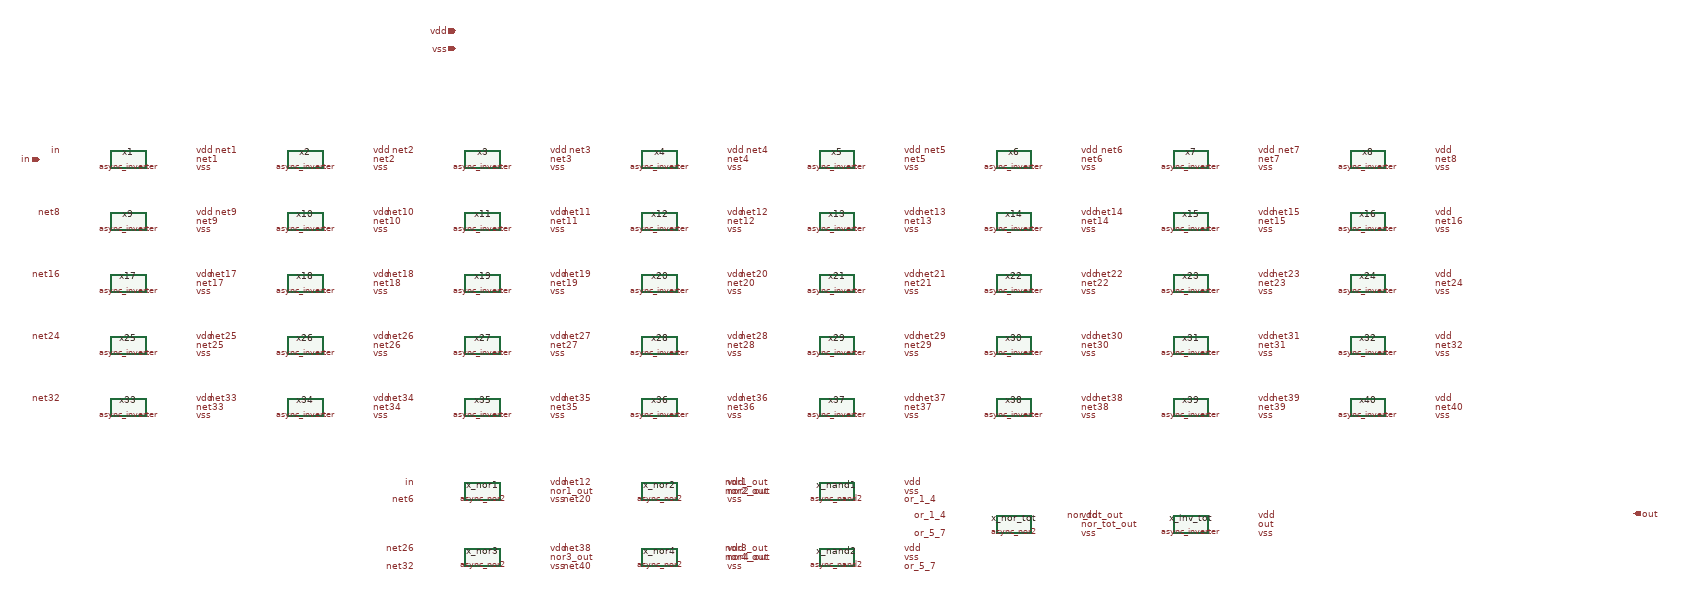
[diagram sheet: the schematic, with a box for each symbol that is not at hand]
v {xschem version=3.4.8RC file_version=1.3}
G {}
K {}
V {}
S {}
F {}
E {}
C {ipin.sym} -1600 -400 0 0 {name=p_in lab=in}
C {iopin.sym} -660 -690 0 0 {name=p_vdd lab=vdd}
C {iopin.sym} -660 -650 0 0 {name=p_vss lab=vss}
C {opin.sym} 2000 400 0 0 {name=p_out lab=out}
C {sar_adc/blocks/async_sar/async_inverter.sym} -1400 -400 0 0 {name=x1}
C {lab_wire.sym} -1550 -420 0 0 {name=l_x1_in lab=in}
C {lab_wire.sym} -1250 -400 2 0 {name=l_x1_out lab=net1}
C {lab_wire.sym} -1250 -420 2 0 {name=l_x1_vdd lab=vdd}
C {lab_wire.sym} -1250 -380 2 0 {name=l_x1_vss lab=vss}
C {sar_adc/blocks/async_sar/async_inverter.sym} -1000 -400 0 0 {name=x2}
C {lab_wire.sym} -1150 -420 0 0 {name=l_x2_in lab=net1}
C {lab_wire.sym} -850 -400 2 0 {name=l_x2_out lab=net2}
C {lab_wire.sym} -850 -420 2 0 {name=l_x2_vdd lab=vdd}
C {lab_wire.sym} -850 -380 2 0 {name=l_x2_vss lab=vss}
C {sar_adc/blocks/async_sar/async_inverter.sym} -600 -400 0 0 {name=x3}
C {lab_wire.sym} -750 -420 0 0 {name=l_x3_in lab=net2}
C {lab_wire.sym} -450 -400 2 0 {name=l_x3_out lab=net3}
C {lab_wire.sym} -450 -420 2 0 {name=l_x3_vdd lab=vdd}
C {lab_wire.sym} -450 -380 2 0 {name=l_x3_vss lab=vss}
C {sar_adc/blocks/async_sar/async_inverter.sym} -200 -400 0 0 {name=x4}
C {lab_wire.sym} -350 -420 0 0 {name=l_x4_in lab=net3}
C {lab_wire.sym} -50 -400 2 0 {name=l_x4_out lab=net4}
C {lab_wire.sym} -50 -420 2 0 {name=l_x4_vdd lab=vdd}
C {lab_wire.sym} -50 -380 2 0 {name=l_x4_vss lab=vss}
C {sar_adc/blocks/async_sar/async_inverter.sym} 200 -400 0 0 {name=x5}
C {lab_wire.sym} 50 -420 0 0 {name=l_x5_in lab=net4}
C {lab_wire.sym} 350 -400 2 0 {name=l_x5_out lab=net5}
C {lab_wire.sym} 350 -420 2 0 {name=l_x5_vdd lab=vdd}
C {lab_wire.sym} 350 -380 2 0 {name=l_x5_vss lab=vss}
C {sar_adc/blocks/async_sar/async_inverter.sym} 600 -400 0 0 {name=x6}
C {lab_wire.sym} 450 -420 0 0 {name=l_x6_in lab=net5}
C {lab_wire.sym} 750 -400 2 0 {name=l_x6_out lab=net6}
C {lab_wire.sym} 750 -420 2 0 {name=l_x6_vdd lab=vdd}
C {lab_wire.sym} 750 -380 2 0 {name=l_x6_vss lab=vss}
C {sar_adc/blocks/async_sar/async_inverter.sym} 1000 -400 0 0 {name=x7}
C {lab_wire.sym} 850 -420 0 0 {name=l_x7_in lab=net6}
C {lab_wire.sym} 1150 -400 2 0 {name=l_x7_out lab=net7}
C {lab_wire.sym} 1150 -420 2 0 {name=l_x7_vdd lab=vdd}
C {lab_wire.sym} 1150 -380 2 0 {name=l_x7_vss lab=vss}
C {sar_adc/blocks/async_sar/async_inverter.sym} 1400 -400 0 0 {name=x8}
C {lab_wire.sym} 1250 -420 0 0 {name=l_x8_in lab=net7}
C {lab_wire.sym} 1550 -400 2 0 {name=l_x8_out lab=net8}
C {lab_wire.sym} 1550 -420 2 0 {name=l_x8_vdd lab=vdd}
C {lab_wire.sym} 1550 -380 2 0 {name=l_x8_vss lab=vss}
C {sar_adc/blocks/async_sar/async_inverter.sym} -1400 -260 0 0 {name=x9}
C {lab_wire.sym} -1550 -280 0 0 {name=l_x9_in lab=net8}
C {lab_wire.sym} -1250 -260 2 0 {name=l_x9_out lab=net9}
C {lab_wire.sym} -1250 -280 2 0 {name=l_x9_vdd lab=vdd}
C {lab_wire.sym} -1250 -240 2 0 {name=l_x9_vss lab=vss}
C {sar_adc/blocks/async_sar/async_inverter.sym} -1000 -260 0 0 {name=x10}
C {lab_wire.sym} -1150 -280 0 0 {name=l_x10_in lab=net9}
C {lab_wire.sym} -850 -260 2 0 {name=l_x10_out lab=net10}
C {lab_wire.sym} -850 -280 2 0 {name=l_x10_vdd lab=vdd}
C {lab_wire.sym} -850 -240 2 0 {name=l_x10_vss lab=vss}
C {sar_adc/blocks/async_sar/async_inverter.sym} -600 -260 0 0 {name=x11}
C {lab_wire.sym} -750 -280 0 0 {name=l_x11_in lab=net10}
C {lab_wire.sym} -450 -260 2 0 {name=l_x11_out lab=net11}
C {lab_wire.sym} -450 -280 2 0 {name=l_x11_vdd lab=vdd}
C {lab_wire.sym} -450 -240 2 0 {name=l_x11_vss lab=vss}
C {sar_adc/blocks/async_sar/async_inverter.sym} -200 -260 0 0 {name=x12}
C {lab_wire.sym} -350 -280 0 0 {name=l_x12_in lab=net11}
C {lab_wire.sym} -50 -260 2 0 {name=l_x12_out lab=net12}
C {lab_wire.sym} -50 -280 2 0 {name=l_x12_vdd lab=vdd}
C {lab_wire.sym} -50 -240 2 0 {name=l_x12_vss lab=vss}
C {sar_adc/blocks/async_sar/async_inverter.sym} 200 -260 0 0 {name=x13}
C {lab_wire.sym} 50 -280 0 0 {name=l_x13_in lab=net12}
C {lab_wire.sym} 350 -260 2 0 {name=l_x13_out lab=net13}
C {lab_wire.sym} 350 -280 2 0 {name=l_x13_vdd lab=vdd}
C {lab_wire.sym} 350 -240 2 0 {name=l_x13_vss lab=vss}
C {sar_adc/blocks/async_sar/async_inverter.sym} 600 -260 0 0 {name=x14}
C {lab_wire.sym} 450 -280 0 0 {name=l_x14_in lab=net13}
C {lab_wire.sym} 750 -260 2 0 {name=l_x14_out lab=net14}
C {lab_wire.sym} 750 -280 2 0 {name=l_x14_vdd lab=vdd}
C {lab_wire.sym} 750 -240 2 0 {name=l_x14_vss lab=vss}
C {sar_adc/blocks/async_sar/async_inverter.sym} 1000 -260 0 0 {name=x15}
C {lab_wire.sym} 850 -280 0 0 {name=l_x15_in lab=net14}
C {lab_wire.sym} 1150 -260 2 0 {name=l_x15_out lab=net15}
C {lab_wire.sym} 1150 -280 2 0 {name=l_x15_vdd lab=vdd}
C {lab_wire.sym} 1150 -240 2 0 {name=l_x15_vss lab=vss}
C {sar_adc/blocks/async_sar/async_inverter.sym} 1400 -260 0 0 {name=x16}
C {lab_wire.sym} 1250 -280 0 0 {name=l_x16_in lab=net15}
C {lab_wire.sym} 1550 -260 2 0 {name=l_x16_out lab=net16}
C {lab_wire.sym} 1550 -280 2 0 {name=l_x16_vdd lab=vdd}
C {lab_wire.sym} 1550 -240 2 0 {name=l_x16_vss lab=vss}
C {sar_adc/blocks/async_sar/async_inverter.sym} -1400 -120 0 0 {name=x17}
C {lab_wire.sym} -1550 -140 0 0 {name=l_x17_in lab=net16}
C {lab_wire.sym} -1250 -120 2 0 {name=l_x17_out lab=net17}
C {lab_wire.sym} -1250 -140 2 0 {name=l_x17_vdd lab=vdd}
C {lab_wire.sym} -1250 -100 2 0 {name=l_x17_vss lab=vss}
C {sar_adc/blocks/async_sar/async_inverter.sym} -1000 -120 0 0 {name=x18}
C {lab_wire.sym} -1150 -140 0 0 {name=l_x18_in lab=net17}
C {lab_wire.sym} -850 -120 2 0 {name=l_x18_out lab=net18}
C {lab_wire.sym} -850 -140 2 0 {name=l_x18_vdd lab=vdd}
C {lab_wire.sym} -850 -100 2 0 {name=l_x18_vss lab=vss}
C {sar_adc/blocks/async_sar/async_inverter.sym} -600 -120 0 0 {name=x19}
C {lab_wire.sym} -750 -140 0 0 {name=l_x19_in lab=net18}
C {lab_wire.sym} -450 -120 2 0 {name=l_x19_out lab=net19}
C {lab_wire.sym} -450 -140 2 0 {name=l_x19_vdd lab=vdd}
C {lab_wire.sym} -450 -100 2 0 {name=l_x19_vss lab=vss}
C {sar_adc/blocks/async_sar/async_inverter.sym} -200 -120 0 0 {name=x20}
C {lab_wire.sym} -350 -140 0 0 {name=l_x20_in lab=net19}
C {lab_wire.sym} -50 -120 2 0 {name=l_x20_out lab=net20}
C {lab_wire.sym} -50 -140 2 0 {name=l_x20_vdd lab=vdd}
C {lab_wire.sym} -50 -100 2 0 {name=l_x20_vss lab=vss}
C {sar_adc/blocks/async_sar/async_inverter.sym} 200 -120 0 0 {name=x21}
C {lab_wire.sym} 50 -140 0 0 {name=l_x21_in lab=net20}
C {lab_wire.sym} 350 -120 2 0 {name=l_x21_out lab=net21}
C {lab_wire.sym} 350 -140 2 0 {name=l_x21_vdd lab=vdd}
C {lab_wire.sym} 350 -100 2 0 {name=l_x21_vss lab=vss}
C {sar_adc/blocks/async_sar/async_inverter.sym} 600 -120 0 0 {name=x22}
C {lab_wire.sym} 450 -140 0 0 {name=l_x22_in lab=net21}
C {lab_wire.sym} 750 -120 2 0 {name=l_x22_out lab=net22}
C {lab_wire.sym} 750 -140 2 0 {name=l_x22_vdd lab=vdd}
C {lab_wire.sym} 750 -100 2 0 {name=l_x22_vss lab=vss}
C {sar_adc/blocks/async_sar/async_inverter.sym} 1000 -120 0 0 {name=x23}
C {lab_wire.sym} 850 -140 0 0 {name=l_x23_in lab=net22}
C {lab_wire.sym} 1150 -120 2 0 {name=l_x23_out lab=net23}
C {lab_wire.sym} 1150 -140 2 0 {name=l_x23_vdd lab=vdd}
C {lab_wire.sym} 1150 -100 2 0 {name=l_x23_vss lab=vss}
C {sar_adc/blocks/async_sar/async_inverter.sym} 1400 -120 0 0 {name=x24}
C {lab_wire.sym} 1250 -140 0 0 {name=l_x24_in lab=net23}
C {lab_wire.sym} 1550 -120 2 0 {name=l_x24_out lab=net24}
C {lab_wire.sym} 1550 -140 2 0 {name=l_x24_vdd lab=vdd}
C {lab_wire.sym} 1550 -100 2 0 {name=l_x24_vss lab=vss}
C {sar_adc/blocks/async_sar/async_inverter.sym} -1400 20 0 0 {name=x25}
C {lab_wire.sym} -1550 0 0 0 {name=l_x25_in lab=net24}
C {lab_wire.sym} -1250 20 2 0 {name=l_x25_out lab=net25}
C {lab_wire.sym} -1250 0 2 0 {name=l_x25_vdd lab=vdd}
C {lab_wire.sym} -1250 40 2 0 {name=l_x25_vss lab=vss}
C {sar_adc/blocks/async_sar/async_inverter.sym} -1000 20 0 0 {name=x26}
C {lab_wire.sym} -1150 0 0 0 {name=l_x26_in lab=net25}
C {lab_wire.sym} -850 20 2 0 {name=l_x26_out lab=net26}
C {lab_wire.sym} -850 0 2 0 {name=l_x26_vdd lab=vdd}
C {lab_wire.sym} -850 40 2 0 {name=l_x26_vss lab=vss}
C {sar_adc/blocks/async_sar/async_inverter.sym} -600 20 0 0 {name=x27}
C {lab_wire.sym} -750 0 0 0 {name=l_x27_in lab=net26}
C {lab_wire.sym} -450 20 2 0 {name=l_x27_out lab=net27}
C {lab_wire.sym} -450 0 2 0 {name=l_x27_vdd lab=vdd}
C {lab_wire.sym} -450 40 2 0 {name=l_x27_vss lab=vss}
C {sar_adc/blocks/async_sar/async_inverter.sym} -200 20 0 0 {name=x28}
C {lab_wire.sym} -350 0 0 0 {name=l_x28_in lab=net27}
C {lab_wire.sym} -50 20 2 0 {name=l_x28_out lab=net28}
C {lab_wire.sym} -50 0 2 0 {name=l_x28_vdd lab=vdd}
C {lab_wire.sym} -50 40 2 0 {name=l_x28_vss lab=vss}
C {sar_adc/blocks/async_sar/async_inverter.sym} 200 20 0 0 {name=x29}
C {lab_wire.sym} 50 0 0 0 {name=l_x29_in lab=net28}
C {lab_wire.sym} 350 20 2 0 {name=l_x29_out lab=net29}
C {lab_wire.sym} 350 0 2 0 {name=l_x29_vdd lab=vdd}
C {lab_wire.sym} 350 40 2 0 {name=l_x29_vss lab=vss}
C {sar_adc/blocks/async_sar/async_inverter.sym} 600 20 0 0 {name=x30}
C {lab_wire.sym} 450 0 0 0 {name=l_x30_in lab=net29}
C {lab_wire.sym} 750 20 2 0 {name=l_x30_out lab=net30}
C {lab_wire.sym} 750 0 2 0 {name=l_x30_vdd lab=vdd}
C {lab_wire.sym} 750 40 2 0 {name=l_x30_vss lab=vss}
C {sar_adc/blocks/async_sar/async_inverter.sym} 1000 20 0 0 {name=x31}
C {lab_wire.sym} 850 0 0 0 {name=l_x31_in lab=net30}
C {lab_wire.sym} 1150 20 2 0 {name=l_x31_out lab=net31}
C {lab_wire.sym} 1150 0 2 0 {name=l_x31_vdd lab=vdd}
C {lab_wire.sym} 1150 40 2 0 {name=l_x31_vss lab=vss}
C {sar_adc/blocks/async_sar/async_inverter.sym} 1400 20 0 0 {name=x32}
C {lab_wire.sym} 1250 0 0 0 {name=l_x32_in lab=net31}
C {lab_wire.sym} 1550 20 2 0 {name=l_x32_out lab=net32}
C {lab_wire.sym} 1550 0 2 0 {name=l_x32_vdd lab=vdd}
C {lab_wire.sym} 1550 40 2 0 {name=l_x32_vss lab=vss}
C {sar_adc/blocks/async_sar/async_inverter.sym} -1400 160 0 0 {name=x33}
C {lab_wire.sym} -1550 140 0 0 {name=l_x33_in lab=net32}
C {lab_wire.sym} -1250 160 2 0 {name=l_x33_out lab=net33}
C {lab_wire.sym} -1250 140 2 0 {name=l_x33_vdd lab=vdd}
C {lab_wire.sym} -1250 180 2 0 {name=l_x33_vss lab=vss}
C {sar_adc/blocks/async_sar/async_inverter.sym} -1000 160 0 0 {name=x34}
C {lab_wire.sym} -1150 140 0 0 {name=l_x34_in lab=net33}
C {lab_wire.sym} -850 160 2 0 {name=l_x34_out lab=net34}
C {lab_wire.sym} -850 140 2 0 {name=l_x34_vdd lab=vdd}
C {lab_wire.sym} -850 180 2 0 {name=l_x34_vss lab=vss}
C {sar_adc/blocks/async_sar/async_inverter.sym} -600 160 0 0 {name=x35}
C {lab_wire.sym} -750 140 0 0 {name=l_x35_in lab=net34}
C {lab_wire.sym} -450 160 2 0 {name=l_x35_out lab=net35}
C {lab_wire.sym} -450 140 2 0 {name=l_x35_vdd lab=vdd}
C {lab_wire.sym} -450 180 2 0 {name=l_x35_vss lab=vss}
C {sar_adc/blocks/async_sar/async_inverter.sym} -200 160 0 0 {name=x36}
C {lab_wire.sym} -350 140 0 0 {name=l_x36_in lab=net35}
C {lab_wire.sym} -50 160 2 0 {name=l_x36_out lab=net36}
C {lab_wire.sym} -50 140 2 0 {name=l_x36_vdd lab=vdd}
C {lab_wire.sym} -50 180 2 0 {name=l_x36_vss lab=vss}
C {sar_adc/blocks/async_sar/async_inverter.sym} 200 160 0 0 {name=x37}
C {lab_wire.sym} 50 140 0 0 {name=l_x37_in lab=net36}
C {lab_wire.sym} 350 160 2 0 {name=l_x37_out lab=net37}
C {lab_wire.sym} 350 140 2 0 {name=l_x37_vdd lab=vdd}
C {lab_wire.sym} 350 180 2 0 {name=l_x37_vss lab=vss}
C {sar_adc/blocks/async_sar/async_inverter.sym} 600 160 0 0 {name=x38}
C {lab_wire.sym} 450 140 0 0 {name=l_x38_in lab=net37}
C {lab_wire.sym} 750 160 2 0 {name=l_x38_out lab=net38}
C {lab_wire.sym} 750 140 2 0 {name=l_x38_vdd lab=vdd}
C {lab_wire.sym} 750 180 2 0 {name=l_x38_vss lab=vss}
C {sar_adc/blocks/async_sar/async_inverter.sym} 1000 160 0 0 {name=x39}
C {lab_wire.sym} 850 140 0 0 {name=l_x39_in lab=net38}
C {lab_wire.sym} 1150 160 2 0 {name=l_x39_out lab=net39}
C {lab_wire.sym} 1150 140 2 0 {name=l_x39_vdd lab=vdd}
C {lab_wire.sym} 1150 180 2 0 {name=l_x39_vss lab=vss}
C {sar_adc/blocks/async_sar/async_inverter.sym} 1400 160 0 0 {name=x40}
C {lab_wire.sym} 1250 140 0 0 {name=l_x40_in lab=net39}
C {lab_wire.sym} 1550 160 2 0 {name=l_x40_out lab=net40}
C {lab_wire.sym} 1550 140 2 0 {name=l_x40_vdd lab=vdd}
C {lab_wire.sym} 1550 180 2 0 {name=l_x40_vss lab=vss}
C {sar_adc/blocks/async_sar/async_nor2.sym} -600 350 0 0 {name=x_nor1}
C {lab_wire.sym} -750 330 0 0 {name=l_n1_a lab=in}
C {lab_wire.sym} -750 370 0 0 {name=l_n1_b lab=net6}
C {lab_wire.sym} -450 330 2 0 {name=l_n1_vd lab=vdd}
C {lab_wire.sym} -450 350 2 0 {name=l_n1_out lab=nor1_out}
C {lab_wire.sym} -450 370 2 0 {name=l_n1_vs lab=vss}
C {sar_adc/blocks/async_sar/async_nor2.sym} -200 350 0 0 {name=x_nor2}
C {lab_wire.sym} -350 330 0 0 {name=l_n2_a lab=net12}
C {lab_wire.sym} -350 370 0 0 {name=l_n2_b lab=net20}
C {lab_wire.sym} -50 330 2 0 {name=l_n2_vd lab=vdd}
C {lab_wire.sym} -50 350 2 0 {name=l_n2_out lab=nor2_out}
C {lab_wire.sym} -50 370 2 0 {name=l_n2_vs lab=vss}
C {sar_adc/blocks/async_sar/async_nand2.sym} 200 350 0 0 {name=x_nand1}
C {lab_wire.sym} 50 330 0 0 {name=l_nd1_a lab=nor1_out}
C {lab_wire.sym} 50 350 0 0 {name=l_nd1_b lab=nor2_out}
C {lab_wire.sym} 350 330 2 0 {name=l_nd1_vd lab=vdd}
C {lab_wire.sym} 350 350 2 0 {name=l_nd1_vs lab=vss}
C {lab_wire.sym} 350 370 2 0 {name=l_nd1_out lab=or_1_4}
C {sar_adc/blocks/async_sar/async_nor2.sym} -600 500 0 0 {name=x_nor3}
C {lab_wire.sym} -750 480 0 0 {name=l_n3_a lab=net26}
C {lab_wire.sym} -750 520 0 0 {name=l_n3_b lab=net32}
C {lab_wire.sym} -450 480 2 0 {name=l_n3_vd lab=vdd}
C {lab_wire.sym} -450 500 2 0 {name=l_n3_out lab=nor3_out}
C {lab_wire.sym} -450 520 2 0 {name=l_n3_vs lab=vss}
C {sar_adc/blocks/async_sar/async_nor2.sym} -200 500 0 0 {name=x_nor4}
C {lab_wire.sym} -350 480 0 0 {name=l_n4_a lab=net38}
C {lab_wire.sym} -350 520 0 0 {name=l_n4_b lab=net40}
C {lab_wire.sym} -50 480 2 0 {name=l_n4_vd lab=vdd}
C {lab_wire.sym} -50 500 2 0 {name=l_n4_out lab=nor4_out}
C {lab_wire.sym} -50 520 2 0 {name=l_n4_vs lab=vss}
C {sar_adc/blocks/async_sar/async_nand2.sym} 200 500 0 0 {name=x_nand2}
C {lab_wire.sym} 50 480 0 0 {name=l_nd2_a lab=nor3_out}
C {lab_wire.sym} 50 500 0 0 {name=l_nd2_b lab=nor4_out}
C {lab_wire.sym} 350 480 2 0 {name=l_nd2_vd lab=vdd}
C {lab_wire.sym} 350 500 2 0 {name=l_nd2_vs lab=vss}
C {lab_wire.sym} 350 520 2 0 {name=l_nd2_out lab=or_5_7}
C {sar_adc/blocks/async_sar/async_nor2.sym} 600 425 0 0 {name=x_nor_tot}
C {lab_wire.sym} 450 405 0 0 {name=l_nt_a lab=or_1_4}
C {lab_wire.sym} 450 445 0 0 {name=l_nt_b lab=or_5_7}
C {lab_wire.sym} 750 405 2 0 {name=l_nt_vd lab=vdd}
C {lab_wire.sym} 750 425 2 0 {name=l_nt_out lab=nor_tot_out}
C {lab_wire.sym} 750 445 2 0 {name=l_nt_vs lab=vss}
C {sar_adc/blocks/async_sar/async_inverter.sym} 1000 425 0 0 {name=x_inv_tot}
C {lab_wire.sym} 850 405 0 0 {name=l_it_in lab=nor_tot_out}
C {lab_wire.sym} 1150 405 2 0 {name=l_it_vd lab=vdd}
C {lab_wire.sym} 1150 425 2 0 {name=l_it_out lab=out}
C {lab_wire.sym} 1150 445 2 0 {name=l_it_vs lab=vss}
